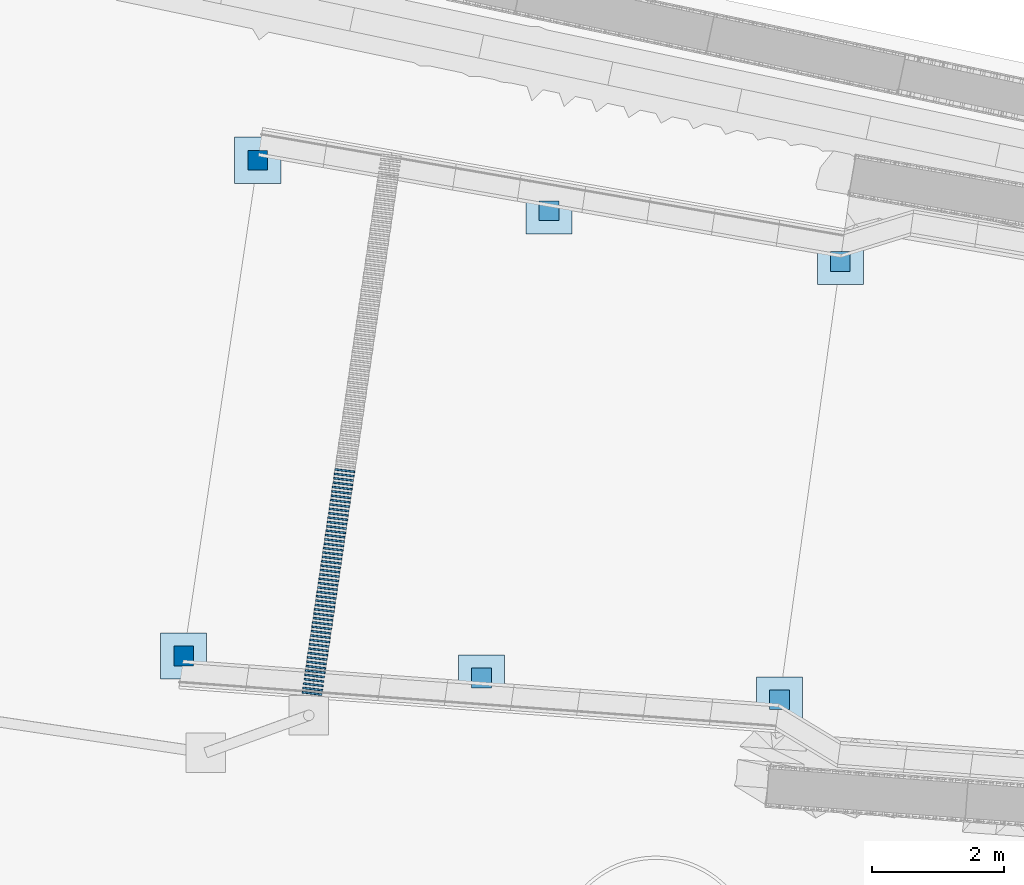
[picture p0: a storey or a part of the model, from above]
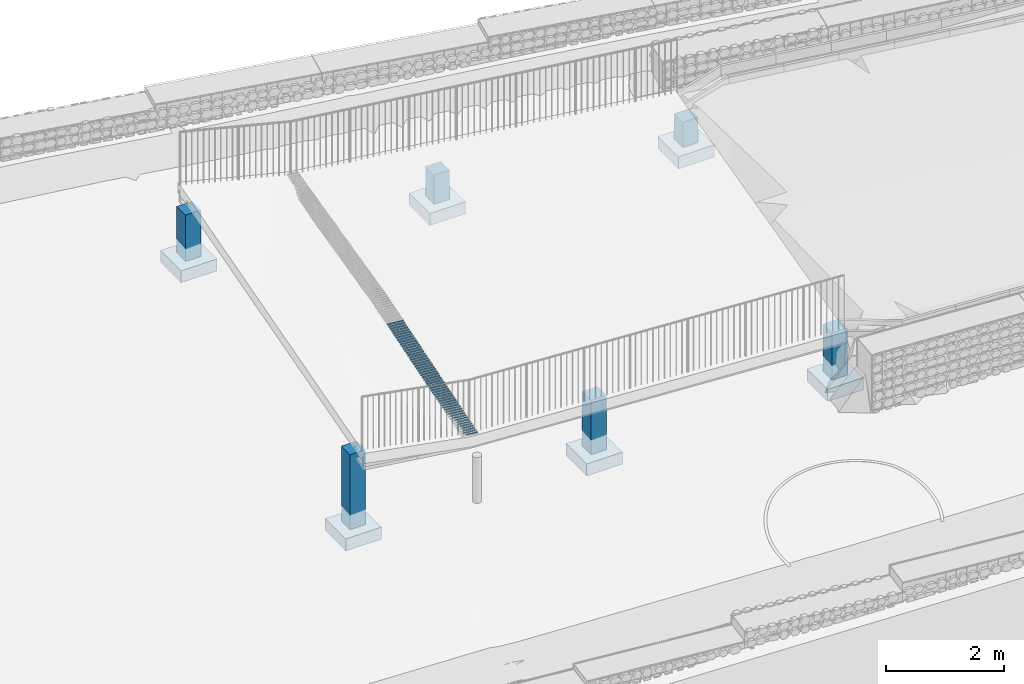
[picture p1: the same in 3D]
Properties of the parts of a building model (IFC4), part 2 of 3

# IfcBuildingElementProxy: Limite south · gabião 27 · pedra aparente
PredefinedType: USERDEFINED; Material: Gabião · pedra irregular
Pset_CasaProvenance - DesignSource: Casa Sobreposta / configuration.json; ReferenceFile: 260617_CasaDFL_Estrutura_Terreno.ifc; ConstructionBasis: DESIGN_ASSUMPTION; Note: R07 concept geometry; dimensions and connections not structurally verified.

# IfcBuildingElementProxy: Limite south · gabião 28 · cesto galvanizado
In: Lares · Rua das Mercês · artigo 4771
PredefinedType: USERDEFINED; Material: Aço galvanizado / Stahl verzinkt
Pset_CasaProvenance - DesignSource: Casa Sobreposta / configuration.json; ReferenceFile: 260617_CasaDFL_Estrutura_Terreno.ifc; ConstructionBasis: DESIGN_ASSUMPTION; Note: R07 concept geometry; dimensions and connections not structurally verified.

# IfcBuildingElementProxy: Limite south · gabião 28 · pedra aparente
In: Lares · Rua das Mercês · artigo 4771
PredefinedType: USERDEFINED; Material: Gabião · pedra irregular
Pset_CasaProvenance - DesignSource: Casa Sobreposta / configuration.json; ReferenceFile: 260617_CasaDFL_Estrutura_Terreno.ifc; ConstructionBasis: DESIGN_ASSUMPTION; Note: R07 concept geometry; dimensions and connections not structurally verified.

# IfcBuildingElementProxy: Limite south · gabião 29 · cesto galvanizado
In: Lares · Rua das Mercês · artigo 4771
PredefinedType: USERDEFINED; Material: Aço galvanizado / Stahl verzinkt
Pset_CasaProvenance - DesignSource: Casa Sobreposta / configuration.json; ReferenceFile: 260617_CasaDFL_Estrutura_Terreno.ifc; ConstructionBasis: DESIGN_ASSUMPTION; Note: R07 concept geometry; dimensions and connections not structurally verified.

# IfcBuildingElementProxy: Limite south · gabião 29 · pedra aparente
In: Lares · Rua das Mercês · artigo 4771
PredefinedType: USERDEFINED; Material: Gabião · pedra irregular
Pset_CasaProvenance - DesignSource: Casa Sobreposta / configuration.json; ReferenceFile: 260617_CasaDFL_Estrutura_Terreno.ifc; ConstructionBasis: DESIGN_ASSUMPTION; Note: R07 concept geometry; dimensions and connections not structurally verified.

# IfcBuildingElementProxy: Limite south · gabião 3 · cesto galvanizado
In: Lares · Rua das Mercês · artigo 4771
PredefinedType: USERDEFINED; Material: Aço galvanizado / Stahl verzinkt
Pset_CasaProvenance - DesignSource: Casa Sobreposta / configuration.json; ReferenceFile: 260617_CasaDFL_Estrutura_Terreno.ifc; ConstructionBasis: DESIGN_ASSUMPTION; Note: R07 concept geometry; dimensions and connections not structurally verified.

# IfcBuildingElementProxy: Limite south · gabião 3 · pedra aparente
In: Lares · Rua das Mercês · artigo 4771
PredefinedType: USERDEFINED; Material: Gabião · pedra irregular
Pset_CasaProvenance - DesignSource: Casa Sobreposta / configuration.json; ReferenceFile: 260617_CasaDFL_Estrutura_Terreno.ifc; ConstructionBasis: DESIGN_ASSUMPTION; Note: R07 concept geometry; dimensions and connections not structurally verified.

# IfcBuildingElementProxy: Limite south · gabião 30 · cesto galvanizado
In: Lares · Rua das Mercês · artigo 4771
PredefinedType: USERDEFINED; Material: Aço galvanizado / Stahl verzinkt
Pset_CasaProvenance - DesignSource: Casa Sobreposta / configuration.json; ReferenceFile: 260617_CasaDFL_Estrutura_Terreno.ifc; ConstructionBasis: DESIGN_ASSUMPTION; Note: R07 concept geometry; dimensions and connections not structurally verified.

# IfcBuildingElementProxy: Limite south · gabião 30 · pedra aparente
In: Lares · Rua das Mercês · artigo 4771
PredefinedType: USERDEFINED; Material: Gabião · pedra irregular
Pset_CasaProvenance - DesignSource: Casa Sobreposta / configuration.json; ReferenceFile: 260617_CasaDFL_Estrutura_Terreno.ifc; ConstructionBasis: DESIGN_ASSUMPTION; Note: R07 concept geometry; dimensions and connections not structurally verified.

# IfcBuildingElementProxy: Limite south · gabião 31 · cesto galvanizado
In: Lares · Rua das Mercês · artigo 4771
PredefinedType: USERDEFINED; Material: Aço galvanizado / Stahl verzinkt
Pset_CasaProvenance - DesignSource: Casa Sobreposta / configuration.json; ReferenceFile: 260617_CasaDFL_Estrutura_Terreno.ifc; ConstructionBasis: DESIGN_ASSUMPTION; Note: R07 concept geometry; dimensions and connections not structurally verified.

# IfcBuildingElementProxy: Limite south · gabião 31 · pedra aparente
In: Lares · Rua das Mercês · artigo 4771
PredefinedType: USERDEFINED; Material: Gabião · pedra irregular
Pset_CasaProvenance - DesignSource: Casa Sobreposta / configuration.json; ReferenceFile: 260617_CasaDFL_Estrutura_Terreno.ifc; ConstructionBasis: DESIGN_ASSUMPTION; Note: R07 concept geometry; dimensions and connections not structurally verified.

# IfcBuildingElementProxy: Limite south · gabião 4 · cesto galvanizado
In: Lares · Rua das Mercês · artigo 4771
PredefinedType: USERDEFINED; Material: Aço galvanizado / Stahl verzinkt
Pset_CasaProvenance - DesignSource: Casa Sobreposta / configuration.json; ReferenceFile: 260617_CasaDFL_Estrutura_Terreno.ifc; ConstructionBasis: DESIGN_ASSUMPTION; Note: R07 concept geometry; dimensions and connections not structurally verified.

# IfcBuildingElementProxy: Limite south · gabião 4 · pedra aparente
In: Lares · Rua das Mercês · artigo 4771
PredefinedType: USERDEFINED; Material: Gabião · pedra irregular
Pset_CasaProvenance - DesignSource: Casa Sobreposta / configuration.json; ReferenceFile: 260617_CasaDFL_Estrutura_Terreno.ifc; ConstructionBasis: DESIGN_ASSUMPTION; Note: R07 concept geometry; dimensions and connections not structurally verified.

# IfcBuildingElementProxy: Limite south · gabião 5 · cesto galvanizado
In: Lares · Rua das Mercês · artigo 4771
PredefinedType: USERDEFINED; Material: Aço galvanizado / Stahl verzinkt
Pset_CasaProvenance - DesignSource: Casa Sobreposta / configuration.json; ReferenceFile: 260617_CasaDFL_Estrutura_Terreno.ifc; ConstructionBasis: DESIGN_ASSUMPTION; Note: R07 concept geometry; dimensions and connections not structurally verified.

# IfcBuildingElementProxy: Limite south · gabião 5 · pedra aparente
In: Lares · Rua das Mercês · artigo 4771
PredefinedType: USERDEFINED; Material: Gabião · pedra irregular
Pset_CasaProvenance - DesignSource: Casa Sobreposta / configuration.json; ReferenceFile: 260617_CasaDFL_Estrutura_Terreno.ifc; ConstructionBasis: DESIGN_ASSUMPTION; Note: R07 concept geometry; dimensions and connections not structurally verified.

# IfcBuildingElementProxy: Limite south · gabião 6 · cesto galvanizado
In: Lares · Rua das Mercês · artigo 4771
PredefinedType: USERDEFINED; Material: Aço galvanizado / Stahl verzinkt
Pset_CasaProvenance - DesignSource: Casa Sobreposta / configuration.json; ReferenceFile: 260617_CasaDFL_Estrutura_Terreno.ifc; ConstructionBasis: DESIGN_ASSUMPTION; Note: R07 concept geometry; dimensions and connections not structurally verified.

# IfcBuildingElementProxy: Limite south · gabião 6 · pedra aparente
In: Lares · Rua das Mercês · artigo 4771
PredefinedType: USERDEFINED; Material: Gabião · pedra irregular
Pset_CasaProvenance - DesignSource: Casa Sobreposta / configuration.json; ReferenceFile: 260617_CasaDFL_Estrutura_Terreno.ifc; ConstructionBasis: DESIGN_ASSUMPTION; Note: R07 concept geometry; dimensions and connections not structurally verified.

# IfcBuildingElementProxy: Limite south · gabião 7 · cesto galvanizado
In: Lares · Rua das Mercês · artigo 4771
PredefinedType: USERDEFINED; Material: Aço galvanizado / Stahl verzinkt
Pset_CasaProvenance - DesignSource: Casa Sobreposta / configuration.json; ReferenceFile: 260617_CasaDFL_Estrutura_Terreno.ifc; ConstructionBasis: DESIGN_ASSUMPTION; Note: R07 concept geometry; dimensions and connections not structurally verified.

# IfcBuildingElementProxy: Limite south · gabião 7 · pedra aparente
In: Lares · Rua das Mercês · artigo 4771
PredefinedType: USERDEFINED; Material: Gabião · pedra irregular
Pset_CasaProvenance - DesignSource: Casa Sobreposta / configuration.json; ReferenceFile: 260617_CasaDFL_Estrutura_Terreno.ifc; ConstructionBasis: DESIGN_ASSUMPTION; Note: R07 concept geometry; dimensions and connections not structurally verified.

# IfcBuildingElementProxy: Limite south · gabião 8 · cesto galvanizado
In: Lares · Rua das Mercês · artigo 4771
PredefinedType: USERDEFINED; Material: Aço galvanizado / Stahl verzinkt
Pset_CasaProvenance - DesignSource: Casa Sobreposta / configuration.json; ReferenceFile: 260617_CasaDFL_Estrutura_Terreno.ifc; ConstructionBasis: DESIGN_ASSUMPTION; Note: R07 concept geometry; dimensions and connections not structurally verified.

# IfcBuildingElementProxy: Limite south · gabião 8 · pedra aparente
In: Lares · Rua das Mercês · artigo 4771
PredefinedType: USERDEFINED; Material: Gabião · pedra irregular
Pset_CasaProvenance - DesignSource: Casa Sobreposta / configuration.json; ReferenceFile: 260617_CasaDFL_Estrutura_Terreno.ifc; ConstructionBasis: DESIGN_ASSUMPTION; Note: R07 concept geometry; dimensions and connections not structurally verified.

# IfcBuildingElementProxy: Limite south · gabião 9 · cesto galvanizado
In: Lares · Rua das Mercês · artigo 4771
PredefinedType: USERDEFINED; Material: Aço galvanizado / Stahl verzinkt
Pset_CasaProvenance - DesignSource: Casa Sobreposta / configuration.json; ReferenceFile: 260617_CasaDFL_Estrutura_Terreno.ifc; ConstructionBasis: DESIGN_ASSUMPTION; Note: R07 concept geometry; dimensions and connections not structurally verified.

# IfcBuildingElementProxy: Limite south · gabião 9 · pedra aparente
In: Lares · Rua das Mercês · artigo 4771
PredefinedType: USERDEFINED; Material: Gabião · pedra irregular
Pset_CasaProvenance - DesignSource: Casa Sobreposta / configuration.json; ReferenceFile: 260617_CasaDFL_Estrutura_Terreno.ifc; ConstructionBasis: DESIGN_ASSUMPTION; Note: R07 concept geometry; dimensions and connections not structurally verified.

# IfcBuildingElementProxy: Limite south · vala de interceção (46)
In: Lares · Rua das Mercês · artigo 4771
PredefinedType: USERDEFINED; Material: Brita drenante
Pset_CasaProvenance - DesignSource: Casa Sobreposta / configuration.json; ReferenceFile: 260617_CasaDFL_Estrutura_Terreno.ifc; ConstructionBasis: DESIGN_ASSUMPTION

# IfcBuildingElementProxy: Trepadeiras · floreira (10)
In: 00 · Habitação e estacionamento
PredefinedType: USERDEFINED; Material: Betão armado / Stahlbeton
Pset_CasaProvenance - DesignSource: Casa Sobreposta / configuration.json; ReferenceFile: 260617_CasaDFL_Estrutura_Terreno.ifc; ConstructionBasis: DESIGN_ASSUMPTION; Note: Indicative planter; soil volume, irrigation, root space and waterproofing to design.

# IfcColumn (57)
Material: Betão armado / Stahlbeton
Pset_CasaProvenance - DesignSource: Casa Sobreposta / configuration.json; ReferenceFile: 260617_CasaDFL_Estrutura_Terreno.ifc
Name | In | ConstructionBasis
18 x Casa térrea · pedestal | 00 · Habitação e estacionamento | ADAPTED_REFERENCE
33 x Pódio suspenso · apoio sobre o terreno | 00 · Habitação e estacionamento | DESIGN_ASSUMPTION
6 x Acesso · apoio do tabuleiro | Lares · Rua das Mercês · artigo 4771 | DESIGN_ASSUMPTION

# IfcColumn: IPE240 / steel (18)
In: 00 · Habitação e estacionamento
Type - Material: Aço pintado / Stahl lackiert
Pset_CasaProvenance - DesignSource: Casa Sobreposta / configuration.json; ReferenceFile: 260617_CasaDFL_Estrutura_Terreno.ifc; ConstructionBasis: ADAPTED_REFERENCE; Note: Reference section; spans, stability and connections require design.

# IfcColumn: RHS80x60x4 / steel (4)
In: 00 · Habitação e estacionamento
Type - Material: Aço pintado / Stahl lackiert
Pset_CasaProvenance - DesignSource: Casa Sobreposta / configuration.json; ReferenceFile: 260617_CasaDFL_Estrutura_Terreno.ifc; ConstructionBasis: DESIGN_ASSUMPTION; Note: Reference section; spans, stability and connections require design.

# IfcColumn: TIMBER0.160x0.160 / timber (24)
In: 00 · Habitação e estacionamento
Type - Material: Madeira / Bauholz
Pset_CasaProvenance - DesignSource: Casa Sobreposta / configuration.json; ReferenceFile: 260617_CasaDFL_Estrutura_Terreno.ifc; ConstructionBasis: DESIGN_ASSUMPTION; Note: Visible timber concept; strength class, deflection, stability, wind and fire design pending.

# IfcCovering (15)
Pset_CasaProvenance - DesignSource: Casa Sobreposta / configuration.json; ReferenceFile: 260617_CasaDFL_Estrutura_Terreno.ifc; ConstructionBasis: DESIGN_ASSUMPTION
Name | In | PredefinedType | Material
2 x Cobertura · forro de madeira | 00 · Habitação e estacionamento | CLADDING | Madeira / Bauholz
2 x Cobertura · isolamento | 00 · Habitação e estacionamento | INSULATION | Lã mineral / Mineralwolle 2
2 x Cobertura · membrana | 00 · Habitação e estacionamento | MEMBRANE | Membrana impermeável — hipótese
Cobertura · telhas individualizadas 1 | 00 · Habitação e estacionamento | ROOFING | Telha cerâmica · tile0 | Pset_CasaProvenance - Note: R07 concept geometry; dimensions and connections not structurally verified.
Cobertura · telhas individualizadas 2 | 00 · Habitação e estacionamento | ROOFING | Telha cerâmica · tile1 | Pset_CasaProvenance - Note: R07 concept geometry; dimensions and connections not structurally verified.
Cobertura · telhas individualizadas 3 | 00 · Habitação e estacionamento | ROOFING | Telha cerâmica · tile2 | Pset_CasaProvenance - Note: R07 concept geometry; dimensions and connections not structurally verified.
Cobertura · cumeeira cerâmica | 00 · Habitação e estacionamento | ROOFING | Telha cerâmica · tile1
Cisterna · camada drenante 100 mm | -01 · Cisterna sob o terraço | FLOORING | Brita drenante
Cisterna · impermeabilização poente | -01 · Cisterna sob o terraço | MEMBRANE | Membrana impermeável — hipótese
Cisterna · impermeabilização norte | -01 · Cisterna sob o terraço | MEMBRANE | Membrana impermeável — hipótese
Cisterna · impermeabilização sul | -01 · Cisterna sob o terraço | MEMBRANE | Membrana impermeável — hipótese
Cisterna · impermeabilização nascente | -01 · Cisterna sob o terraço | MEMBRANE | Membrana impermeável — hipótese

# IfcDoor (18)
In: 00 · Habitação e estacionamento
PredefinedType: DOOR
Pset_CasaProvenance - DesignSource: Casa Sobreposta / configuration.json; ReferenceFile: 260617_CasaDFL_Estrutura_Terreno.ifc
Name | OverallHeight (m) | OverallWidth (m) | OperationType | Material | ConstructionBasis
Porta interior 1 | 2.1 | 0.830093 | SINGLE_SWING_LEFT | OSB | ADAPTED_REFERENCE
Porta interior 2 | 2.1 | 0.830093 | SINGLE_SWING_LEFT | OSB | ADAPTED_REFERENCE
Porta interior 3 | 2.1 | 0.730086 | SINGLE_SWING_LEFT | OSB | ADAPTED_REFERENCE
Porta interior 4 | 2.1 | 0.830092 | SINGLE_SWING_LEFT | OSB | ADAPTED_REFERENCE
Porta interior 5 | 2.1 | 0.830077 | SINGLE_SWING_LEFT | OSB | ADAPTED_REFERENCE
Porta interior 6 | 2.1 | 0.730017 | SINGLE_SWING_LEFT | OSB | ADAPTED_REFERENCE
Porta do estacionamento | 2.1 | 0.83 | SINGLE_SWING_LEFT | Aço pintado / Stahl lackiert | ADAPTED_REFERENCE
Folha de correr sul 2 | 3 | 1.97133 | SLIDING_TO_LEFT | Vidro / Normalglas | DESIGN_ASSUMPTION
Folha de correr sul 4 | 3 | 1.97133 | SLIDING_TO_LEFT | Vidro / Normalglas | DESIGN_ASSUMPTION
Folha de correr sul 6 | 3 | 1.97133 | SLIDING_TO_LEFT | Vidro / Normalglas | DESIGN_ASSUMPTION
Folha de correr sul 8 | 3 | 1.97133 | SLIDING_TO_LEFT | Vidro / Normalglas | DESIGN_ASSUMPTION
Folha de correr sul 10 | 3 | 1.97133 | SLIDING_TO_LEFT | Vidro / Normalglas | DESIGN_ASSUMPTION
Folha de correr sul 12 | 3 | 0.614 | SLIDING_TO_LEFT | Vidro / Normalglas | DESIGN_ASSUMPTION
Fachada poente integralmente envidraçada · módulo 4 | 3 | 1.55 | SLIDING_TO_LEFT | Vidro / Normalglas | DESIGN_ASSUMPTION | Pset_CasaGlazedFacade - Revision: R02 · kiwi pergola; Facade: WEST / highlighted end in user sketch; Infill: Full-height glazing; no opaque infill; GlazingSpecification: 8 mm nominal representation only; insulated safety glazing assembly to specify
2 x Contentor · porta dupla | 2.39 | 1.17 | SINGLE_SWING_LEFT | Contentor · pintura 1 | DESIGN_ASSUMPTION
2 x Contentor · porta dupla | 2.39 | 1.17 | SINGLE_SWING_LEFT | Contentor · pintura 2 | DESIGN_ASSUMPTION

# IfcElementAssembly: Acesso · guarda lateral do troço suspenso (6)
In: Lares · Rua das Mercês · artigo 4771
PredefinedType: USERDEFINED
Pset_CasaProvenance - DesignSource: Casa Sobreposta / configuration.json; ReferenceFile: 260617_CasaDFL_Estrutura_Terreno.ifc; ConstructionBasis: DESIGN_ASSUMPTION

# IfcElementAssembly: CISTERN_PODIUM, Pódio · terraço, casa térrea e cisterna
In: 00 · Habitação e estacionamento
PredefinedType: USERDEFINED
Pset_CasaProvenance - DesignSource: Casa Sobreposta / configuration.json; ReferenceFile: 260617_CasaDFL_Estrutura_Terreno.ifc; ConstructionBasis: DESIGN_ASSUMPTION
Pset_CasaUndercroft - NaturalGroundRetained: yes; EnclosedStorage: no; Use: Open ventilated sloping void; not a habitable or storage storey; StructuralStatus: Concept slab, beams, piers and foundation sizes; geotechnical and structural design pending
Pset_CasaPodium - TankGrossPlan_m2: 23; TankBaseLevel_m: 13.2; MinimumInternalHeight_m: 2.31; FloorSupport: Entire podium suspended on discrete supports above natural slope; PlanningAssumption: Cistern excluded from 250 m2 by explicit user confirmation 2026-10-02

# IfcElementAssembly: COVERED_PODIUM_BALCONY, Varanda coberta · continuação integral da cobertura
In: 00 · Habitação e estacionamento
PredefinedType: USERDEFINED
Pset_CasaProvenance - DesignSource: Casa Sobreposta / configuration.json; ReferenceFile: 260617_CasaDFL_Estrutura_Terreno.ifc; ConstructionBasis: DESIGN_ASSUMPTION

# IfcElementAssembly: EXISTING_SHIPPING_CONTAINER (2)
In: 00 · Habitação e estacionamento
PredefinedType: USERDEFINED
Pset_CasaProvenance - DesignSource: Casa Sobreposta / configuration.json; ReferenceFile: 260617_CasaDFL_Estrutura_Terreno.ifc; ConstructionBasis: DESIGN_ASSUMPTION
Pset_CasaExistingContext - Length_m: 6; WidthAssumed_m: 2.44; HeightAssumed_m: 2.59; Location: Digitised visible roofs from signed orthophoto; fitted 6 x 2.44 m, provisional +/- 0.50 m, verify ground corners; Status: Existing context; not included in new building setback or new floor-area schedule; Colour: Illustrative, condition not surveyed
Name
Contentor existente 1 · 6 m
Contentor existente 2 · 6 m

# IfcElementAssembly: LIVING_SHADE_TRELLIS, Fachada sul e pátio · estrutura e trepadeiras
In: 00 · Habitação e estacionamento
PredefinedType: USERDEFINED
Pset_CasaProvenance - DesignSource: Casa Sobreposta / configuration.json; ReferenceFile: 260617_CasaDFL_Estrutura_Terreno.ifc; ConstructionBasis: DESIGN_ASSUMPTION

# IfcFooting (73)
Material: Betão armado / Stahlbeton
Pset_CasaProvenance - DesignSource: Casa Sobreposta / configuration.json; ReferenceFile: 260617_CasaDFL_Estrutura_Terreno.ifc
Name | In | PredefinedType | ConstructionBasis
18 x Casa térrea · sapata | 00 · Habitação e estacionamento | PAD_FOOTING | ADAPTED_REFERENCE
Cisterna · sapata corrida poente | -01 · Cisterna sob o terraço | STRIP_FOOTING | DESIGN_ASSUMPTION
Cisterna · sapata corrida norte | -01 · Cisterna sob o terraço | STRIP_FOOTING | DESIGN_ASSUMPTION
Cisterna · sapata corrida sul | -01 · Cisterna sob o terraço | STRIP_FOOTING | DESIGN_ASSUMPTION
Cisterna · sapata corrida nascente | -01 · Cisterna sob o terraço | STRIP_FOOTING | DESIGN_ASSUMPTION
4 x Jardim · apoio | 00 · Habitação e estacionamento | PAD_FOOTING | DESIGN_ASSUMPTION
33 x Pódio suspenso · sapata pontual | 00 · Habitação e estacionamento | PAD_FOOTING | DESIGN_ASSUMPTION
8 x Contentor · apoio existente indicativo | 00 · Habitação e estacionamento | PAD_FOOTING | DESIGN_ASSUMPTION
6 x Acesso · sapata pontual | Lares · Rua das Mercês · artigo 4771 | PAD_FOOTING | DESIGN_ASSUMPTION

# IfcFurnishingElement, Ilha da cozinha · esquema
In: 00 · Habitação e estacionamento
Material: OSB
Pset_CasaProvenance - DesignSource: Casa Sobreposta / configuration.json; ReferenceFile: 260617_CasaDFL_Estrutura_Terreno.ifc; ConstructionBasis: ADAPTED_REFERENCE

# IfcGeographicElement, Terreno · R07 com telha, cisterna e drenagem
In: Lares · Rua das Mercês · artigo 4771
PredefinedType: TERRAIN; Material: Terreno · modelação proposta
Pset_CasaProvenance - DesignSource: Casa Sobreposta / configuration.json; ReferenceFile: 260617_CasaDFL_Estrutura_Terreno.ifc; ConstructionBasis: DESIGN_ASSUMPTION

# IfcGeographicElement: ANALYTICAL_CUT_VOLUME, Escavação · diferença entre terrenos
In: Lares · Rua das Mercês · artigo 4771
PredefinedType: USERDEFINED; Material: Escavação · volume analítico
Pset_CasaProvenance - DesignSource: Casa Sobreposta / configuration.json; ReferenceFile: 260617_CasaDFL_Estrutura_Terreno.ifc; ConstructionBasis: DESIGN_ASSUMPTION; Note: ANALYTICAL VOLUME, not additional constructed material. Closed wedges between surveyed and proposed TIN, split where sign changes. Excludes stripping, foundations, services and bulking.
Pset_CasaEarthworks - Kind: CUT; Volume_m3: 45.8495; Method: Exact signed integration of linear proposed/existing display TIN, splitting zero crossings; Excluded: Topsoil stripping, foundation/service trenches, soil replacement, bulking and shrinkage; Status: CONCEPT_GEOMETRIC_VOLUME; not a measured bill of works; DefaultVisibility: Hide analytical volumes in normal model views
Qto_CasaEarthworks - NetVolume: 45.8495 m3

# IfcGeographicElement: ANALYTICAL_FILL_VOLUME, Aterro · diferença entre terrenos
In: Lares · Rua das Mercês · artigo 4771
PredefinedType: USERDEFINED; Material: Aterro · volume analítico
Pset_CasaProvenance - DesignSource: Casa Sobreposta / configuration.json; ReferenceFile: 260617_CasaDFL_Estrutura_Terreno.ifc; ConstructionBasis: DESIGN_ASSUMPTION; Note: ANALYTICAL VOLUME, not additional constructed material. Closed wedges between surveyed and proposed TIN, split where sign changes. Excludes stripping, foundations, services and bulking.
Pset_CasaEarthworks - Kind: FILL; Volume_m3: 34.1829; Method: Exact signed integration of linear proposed/existing display TIN, splitting zero crossings; Excluded: Topsoil stripping, foundation/service trenches, soil replacement, bulking and shrinkage; Status: CONCEPT_GEOMETRIC_VOLUME; not a measured bill of works; DefaultVisibility: Hide analytical volumes in normal model views
Qto_CasaEarthworks - NetVolume: 34.1829 m3

# IfcGeographicElement: Acesso trapezoidal · 8,60 m no pódio / 5,00 m na rua
In: Lares · Rua das Mercês · artigo 4771
PredefinedType: USERDEFINED; Material: Pavimento rugoso · betão vassourado
Pset_CasaProvenance - DesignSource: Casa Sobreposta / configuration.json; ReferenceFile: 260617_CasaDFL_Estrutura_Terreno.ifc; ConstructionBasis: DESIGN_ASSUMPTION

# IfcGeographicElement: Marcação no solo · árvore indicativa 01
In: Lares · Rua das Mercês · artigo 4771
PredefinedType: USERDEFINED; Material: Marcação de plantação · linha no terreno
Pset_CasaProvenance - DesignSource: Casa Sobreposta / configuration.json; ReferenceFile: 260617_CasaDFL_Estrutura_Terreno.ifc; ConstructionBasis: DESIGN_ASSUMPTION; Note: R07 concept geometry; dimensions and connections not structurally verified.
Pset_PlantingReserve - Diameter_m: 3; Representation: GROUND_CIRCLE_ONLY; Species: UNSPECIFIED; Status: Indicative position and spacing, not a mature canopy guarantee

# IfcGeographicElement: Marcação no solo · árvore indicativa 02
In: Lares · Rua das Mercês · artigo 4771
PredefinedType: USERDEFINED; Material: Marcação de plantação · linha no terreno
Pset_CasaProvenance - DesignSource: Casa Sobreposta / configuration.json; ReferenceFile: 260617_CasaDFL_Estrutura_Terreno.ifc; ConstructionBasis: DESIGN_ASSUMPTION; Note: R07 concept geometry; dimensions and connections not structurally verified.
Pset_PlantingReserve - Diameter_m: 3; Representation: GROUND_CIRCLE_ONLY; Species: UNSPECIFIED; Status: Indicative position and spacing, not a mature canopy guarantee

# IfcGeographicElement: Marcação no solo · árvore indicativa 03
In: Lares · Rua das Mercês · artigo 4771
PredefinedType: USERDEFINED; Material: Marcação de plantação · linha no terreno
Pset_CasaProvenance - DesignSource: Casa Sobreposta / configuration.json; ReferenceFile: 260617_CasaDFL_Estrutura_Terreno.ifc; ConstructionBasis: DESIGN_ASSUMPTION; Note: R07 concept geometry; dimensions and connections not structurally verified.
Pset_PlantingReserve - Diameter_m: 3; Representation: GROUND_CIRCLE_ONLY; Species: UNSPECIFIED; Status: Indicative position and spacing, not a mature canopy guarantee

# IfcGeographicElement: Marcação no solo · árvore indicativa 04
In: Lares · Rua das Mercês · artigo 4771
PredefinedType: USERDEFINED; Material: Marcação de plantação · linha no terreno
Pset_CasaProvenance - DesignSource: Casa Sobreposta / configuration.json; ReferenceFile: 260617_CasaDFL_Estrutura_Terreno.ifc; ConstructionBasis: DESIGN_ASSUMPTION; Note: R07 concept geometry; dimensions and connections not structurally verified.
Pset_PlantingReserve - Diameter_m: 3; Representation: GROUND_CIRCLE_ONLY; Species: UNSPECIFIED; Status: Indicative position and spacing, not a mature canopy guarantee

# IfcGeographicElement: Marcação no solo · árvore indicativa 05
In: Lares · Rua das Mercês · artigo 4771
PredefinedType: USERDEFINED; Material: Marcação de plantação · linha no terreno
Pset_CasaProvenance - DesignSource: Casa Sobreposta / configuration.json; ReferenceFile: 260617_CasaDFL_Estrutura_Terreno.ifc; ConstructionBasis: DESIGN_ASSUMPTION; Note: R07 concept geometry; dimensions and connections not structurally verified.
Pset_PlantingReserve - Diameter_m: 3; Representation: GROUND_CIRCLE_ONLY; Species: UNSPECIFIED; Status: Indicative position and spacing, not a mature canopy guarantee

# IfcGeographicElement: Marcação no solo · árvore indicativa 06
In: Lares · Rua das Mercês · artigo 4771
PredefinedType: USERDEFINED; Material: Marcação de plantação · linha no terreno
Pset_CasaProvenance - DesignSource: Casa Sobreposta / configuration.json; ReferenceFile: 260617_CasaDFL_Estrutura_Terreno.ifc; ConstructionBasis: DESIGN_ASSUMPTION; Note: R07 concept geometry; dimensions and connections not structurally verified.
Pset_PlantingReserve - Diameter_m: 3; Representation: GROUND_CIRCLE_ONLY; Species: UNSPECIFIED; Status: Indicative position and spacing, not a mature canopy guarantee

# IfcGeographicElement: Marcação no solo · árvore indicativa 07
In: Lares · Rua das Mercês · artigo 4771
PredefinedType: USERDEFINED; Material: Marcação de plantação · linha no terreno
Pset_CasaProvenance - DesignSource: Casa Sobreposta / configuration.json; ReferenceFile: 260617_CasaDFL_Estrutura_Terreno.ifc; ConstructionBasis: DESIGN_ASSUMPTION; Note: R07 concept geometry; dimensions and connections not structurally verified.
Pset_PlantingReserve - Diameter_m: 3; Representation: GROUND_CIRCLE_ONLY; Species: UNSPECIFIED; Status: Indicative position and spacing, not a mature canopy guarantee

# IfcGeographicElement: Marcação no solo · árvore indicativa 08
In: Lares · Rua das Mercês · artigo 4771
PredefinedType: USERDEFINED; Material: Marcação de plantação · linha no terreno
Pset_CasaProvenance - DesignSource: Casa Sobreposta / configuration.json; ReferenceFile: 260617_CasaDFL_Estrutura_Terreno.ifc; ConstructionBasis: DESIGN_ASSUMPTION; Note: R07 concept geometry; dimensions and connections not structurally verified.
Pset_PlantingReserve - Diameter_m: 3; Representation: GROUND_CIRCLE_ONLY; Species: UNSPECIFIED; Status: Indicative position and spacing, not a mature canopy guarantee

# IfcGeographicElement: Marcação no solo · árvore indicativa 09
In: Lares · Rua das Mercês · artigo 4771
PredefinedType: USERDEFINED; Material: Marcação de plantação · linha no terreno
Pset_CasaProvenance - DesignSource: Casa Sobreposta / configuration.json; ReferenceFile: 260617_CasaDFL_Estrutura_Terreno.ifc; ConstructionBasis: DESIGN_ASSUMPTION; Note: R07 concept geometry; dimensions and connections not structurally verified.
Pset_PlantingReserve - Diameter_m: 3; Representation: GROUND_CIRCLE_ONLY; Species: UNSPECIFIED; Status: Indicative position and spacing, not a mature canopy guarantee

# IfcGeographicElement: Marcação no solo · árvore indicativa 10
In: Lares · Rua das Mercês · artigo 4771
PredefinedType: USERDEFINED; Material: Marcação de plantação · linha no terreno
Pset_CasaProvenance - DesignSource: Casa Sobreposta / configuration.json; ReferenceFile: 260617_CasaDFL_Estrutura_Terreno.ifc; ConstructionBasis: DESIGN_ASSUMPTION; Note: R07 concept geometry; dimensions and connections not structurally verified.
Pset_PlantingReserve - Diameter_m: 3; Representation: GROUND_CIRCLE_ONLY; Species: UNSPECIFIED; Status: Indicative position and spacing, not a mature canopy guarantee

# IfcGeographicElement: VEGETATION, Trepadeiras · folhas individuais, estado ilustrativo
In: 00 · Habitação e estacionamento
PredefinedType: USERDEFINED; Material: Folhagem · trepadeiras
Pset_CasaProvenance - DesignSource: Casa Sobreposta / configuration.json; ReferenceFile: 260617_CasaDFL_Estrutura_Terreno.ifc; ConstructionBasis: DESIGN_ASSUMPTION; Note: Procedural leaves for visual intent only; no predicted growth, species performance or wind protection.

# IfcMember (154)
In: 00 · Habitação e estacionamento
Pset_CasaProvenance - DesignSource: Casa Sobreposta / configuration.json; ReferenceFile: 260617_CasaDFL_Estrutura_Terreno.ifc; ConstructionBasis: DESIGN_ASSUMPTION
Name | Material
4 x Contentor · canto | Contentor · pintura 1
50 x Contentor · nervura lateral | Contentor · pintura 1
23 x Contentor · nervura cobertura | Contentor · pintura 1
4 x Contentor · canto | Contentor · pintura 2
50 x Contentor · nervura lateral | Contentor · pintura 2
23 x Contentor · nervura cobertura | Contentor · pintura 2

# IfcMember: C240 / steel (2)
In: 00 · Habitação e estacionamento
Type - Material: Aço pintado / Stahl lackiert
Pset_CasaProvenance - DesignSource: Casa Sobreposta / configuration.json; ReferenceFile: 260617_CasaDFL_Estrutura_Terreno.ifc; ConstructionBasis: ADAPTED_REFERENCE; Note: Reference section; spans, stability and connections require design.

# IfcMember: D0.004 / galvanized (117)
In: 00 · Habitação e estacionamento
Type - Material: Aço galvanizado / Stahl verzinkt
Pset_CasaProvenance - DesignSource: Casa Sobreposta / configuration.json; ReferenceFile: 260617_CasaDFL_Estrutura_Terreno.ifc; ConstructionBasis: DESIGN_ASSUMPTION; Note: Reference section; spans, stability and connections require design.
Name
50 x Trepadeiras · fio horizontal
67 x Trepadeiras · fio vertical

# IfcMember: D0.015 / vine_wood (627)
In: 00 · Habitação e estacionamento
Type - Material: Ramos de trepadeiras
Pset_CasaProvenance - DesignSource: Casa Sobreposta / configuration.json; ReferenceFile: 260617_CasaDFL_Estrutura_Terreno.ifc; ConstructionBasis: DESIGN_ASSUMPTION; Note: Reference section; spans, stability and connections require design.

# IfcMember: D0.025 / galvanized (8)
In: 00 · Habitação e estacionamento
Type - Material: Aço galvanizado / Stahl verzinkt
Pset_CasaProvenance - DesignSource: Casa Sobreposta / configuration.json; ReferenceFile: 260617_CasaDFL_Estrutura_Terreno.ifc; ConstructionBasis: DESIGN_ASSUMPTION; Note: Reference section; spans, stability and connections require design.

# IfcMember: R0.025 / galvanized (212)
Type - Material: Aço galvanizado / Stahl verzinkt
Pset_CasaProvenance - DesignSource: Casa Sobreposta / configuration.json; ReferenceFile: 260617_CasaDFL_Estrutura_Terreno.ifc; ConstructionBasis: DESIGN_ASSUMPTION; Note: Reference section; spans, stability and connections require design.
Name | In
8 x Cobertura · fita de contraventamento | 00 · Habitação e estacionamento
80 x Interceção · grelha rua | Lares · Rua das Mercês · artigo 4771
124 x Interceção · grelha estacionamento | Lares · Rua das Mercês · artigo 4771

# IfcMember: R0.035 / steel (68)
In: 00 · Habitação e estacionamento
Type - Material: Aço pintado / Stahl lackiert
Pset_CasaProvenance - DesignSource: Casa Sobreposta / configuration.json; ReferenceFile: 260617_CasaDFL_Estrutura_Terreno.ifc; ConstructionBasis: ADAPTED_REFERENCE; Note: Reference section; spans, stability and connections require design.
Name
2 x Rasgo norte 1 · montante
2 x Rasgo norte 1 · travessa
2 x Rasgo norte 2 · montante
2 x Rasgo norte 2 · travessa
2 x Rasgo norte 3 · montante
2 x Rasgo norte 3 · travessa
2 x Rasgo norte 4 · montante
2 x Rasgo norte 4 · travessa
2 x Rasgo norte 5 · montante
2 x Rasgo norte 5 · travessa
2 x Rasgo norte 6 · montante
2 x Rasgo norte 6 · travessa
2 x Rasgo norte 7 · montante
2 x Rasgo norte 7 · travessa
2 x Folha de correr sul 2 · montante
2 x Folha de correr sul 2 · travessa
2 x Folha de correr sul 4 · montante
2 x Folha de correr sul 4 · travessa
2 x Folha de correr sul 6 · montante
2 x Folha de correr sul 6 · travessa
2 x Folha de correr sul 8 · montante
2 x Folha de correr sul 8 · travessa
2 x Folha de correr sul 10 · montante
2 x Folha de correr sul 10 · travessa
2 x Folha de correr sul 12 · montante
2 x Folha de correr sul 12 · travessa
2 x Fachada poente integralmente envidraçada · módulo 1 · montante
2 x Fachada poente integralmente envidraçada · módulo 1 · travessa
2 x Fachada poente integralmente envidraçada · módulo 2 · montante
2 x Fachada poente integralmente envidraçada · módulo 2 · travessa
2 x Fachada poente integralmente envidraçada · módulo 3 · montante
2 x Fachada poente integralmente envidraçada · módulo 3 · travessa
2 x Fachada poente integralmente envidraçada · módulo 4 · montante
2 x Fachada poente integralmente envidraçada · módulo 4 · travessa

# IfcMember: TIMBER0.045x0.060 / timber (30)
In: 00 · Habitação e estacionamento
Type - Material: Madeira / Bauholz
Pset_CasaProvenance - DesignSource: Casa Sobreposta / configuration.json; ReferenceFile: 260617_CasaDFL_Estrutura_Terreno.ifc; ConstructionBasis: DESIGN_ASSUMPTION; Note: Visible timber concept; strength class, deflection, stability, wind and fire design pending.

# IfcMember: TIMBER0.080x0.240 / timber (134)
In: 00 · Habitação e estacionamento
Type - Material: Madeira / Bauholz
Pset_CasaProvenance - DesignSource: Casa Sobreposta / configuration.json; ReferenceFile: 260617_CasaDFL_Estrutura_Terreno.ifc; ConstructionBasis: DESIGN_ASSUMPTION; Note: Visible timber concept; strength class, deflection, stability, wind and fire design pending.

# IfcMember: TIMBER0.100x0.160 / timber (24)
In: 00 · Habitação e estacionamento
Type - Material: Madeira / Bauholz
Pset_CasaProvenance - DesignSource: Casa Sobreposta / configuration.json; ReferenceFile: 260617_CasaDFL_Estrutura_Terreno.ifc; ConstructionBasis: DESIGN_ASSUMPTION; Note: Visible timber concept; strength class, deflection, stability, wind and fire design pending.

# IfcMember: TIMBER0.140x0.140 / timber (12)
In: 00 · Habitação e estacionamento
Type - Material: Madeira / Bauholz
Pset_CasaProvenance - DesignSource: Casa Sobreposta / configuration.json; ReferenceFile: 260617_CasaDFL_Estrutura_Terreno.ifc; ConstructionBasis: DESIGN_ASSUMPTION; Note: Visible timber concept; strength class, deflection, stability, wind and fire design pending.

# IfcMember: TIMBER0.160x0.240 / timber (24)
In: 00 · Habitação e estacionamento
Type - Material: Madeira / Bauholz
Pset_CasaProvenance - DesignSource: Casa Sobreposta / configuration.json; ReferenceFile: 260617_CasaDFL_Estrutura_Terreno.ifc; ConstructionBasis: DESIGN_ASSUMPTION; Note: Visible timber concept; strength class, deflection, stability, wind and fire design pending.

# IfcOpeningElement (20)
In: 00 · Habitação e estacionamento
PredefinedType: OPENING
Pset_CasaProvenance - DesignSource: Casa Sobreposta / configuration.json; ReferenceFile: 260617_CasaDFL_Estrutura_Terreno.ifc; ConstructionBasis: DESIGN_ASSUMPTION; Note: Real subtractive void
Name
Vão porta interior 1.1
Vão porta interior 1.2
Vão porta interior 2.1
Vão porta interior 2.2
Vão porta interior 3.1
Vão porta interior 3.2
Vão porta interior 4.1
Vão porta interior 4.2
Vão porta interior 5.1
Vão porta interior 6.1
Vão porta interior 6.2
Vão rasgo norte 1
Vão rasgo norte 2
Vão rasgo norte 3
Vão rasgo norte 4
Vão rasgo norte 5
Vão rasgo norte 6
Vão rasgo norte 7
Vão de acesso do estacionamento
Cisterna · abertura de inspeção

# IfcPipeSegment: D0.10 / galvanized (6)
In: 00 · Habitação e estacionamento
Type - Material: Aço galvanizado / Stahl verzinkt
Pset_CasaProvenance - DesignSource: Casa Sobreposta / configuration.json; ReferenceFile: 260617_CasaDFL_Estrutura_Terreno.ifc; ConstructionBasis: DESIGN_ASSUMPTION; Note: Nominal route to rainwater tank; Nominal gutter fall 0.2% to west; filter, first flush, sizing and overflow to detail. Separate from vehicle drainage.

# IfcPipeSegment: D0.16 / drain (4)
In: Lares · Rua das Mercês · artigo 4771
Type - Material: Caleiras · betão
Pset_CasaProvenance - DesignSource: Casa Sobreposta / configuration.json; ReferenceFile: 260617_CasaDFL_Estrutura_Terreno.ifc; ConstructionBasis: DESIGN_ASSUMPTION
Name | Note
Acesso · queda pluvial até coletor | Reference section; spans, stability and connections require design.
3 x Acesso · coletor separado da cisterna | Nominal DN160 spatial route only, not hydraulically sized. Silt/contaminant treatment and outlet/infiltration to design.

# IfcPlate (50)
In: 00 · Habitação e estacionamento
Pset_CasaProvenance - DesignSource: Casa Sobreposta / configuration.json; ReferenceFile: 260617_CasaDFL_Estrutura_Terreno.ifc; ConstructionBasis: DESIGN_ASSUMPTION
Name | PredefinedType | Material
18 x Cobertura · ligação madeira aço | SHEET | Aço galvanizado / Stahl verzinkt
Empena poente envidraçada | SHEET | Vidro / Normalglas
Cisterna · tampa estanque de inspeção | SHEET | Aço galvanizado / Stahl verzinkt | Pset_CasaProvenance - Note: Flush, closed 900 mm maintenance hatch; cover capacity and safe maintenance access to detail. Not a routine entrance.
24 x Varanda coberta · base metálica | SHEET | Aço galvanizado / Stahl verzinkt
2 x Contentor · chapa lateral |  | Contentor · pintura 1
Contentor · chapa de fundo |  | Contentor · pintura 1
2 x Contentor · chapa lateral |  | Contentor · pintura 2
Contentor · chapa de fundo |  | Contentor · pintura 2

# IfcRailing (14)
PredefinedType: GUARDRAIL; Material: Aço pintado / Stahl lackiert
Pset_CasaProvenance - DesignSource: Casa Sobreposta / configuration.json; ReferenceFile: 260617_CasaDFL_Estrutura_Terreno.ifc; ConstructionBasis: DESIGN_ASSUMPTION; Note: Study guard 1.10 m; twin handrails at 0.70 and 0.90 m on ramp; loads and fixings unverified.
Name | In
Pódio · guarda sul | 00 · Habitação e estacionamento
Pódio · guarda poente sul | 00 · Habitação e estacionamento
Pódio · guarda poente norte | 00 · Habitação e estacionamento
Pódio · guarda norte | 00 · Habitação e estacionamento
2 x Jardim · corrimão poente | 00 · Habitação e estacionamento
2 x Jardim · guarda do patamar | 00 · Habitação e estacionamento
6 x Acesso · guarda lateral | Lares · Rua das Mercês · artigo 4771

# IfcRoof, Cobertura de telha · duas águas 30 graus
In: 00 · Habitação e estacionamento
PredefinedType: GABLE_ROOF; Material: Madeira / Bauholz
Pset_CasaProvenance - DesignSource: Casa Sobreposta / configuration.json; ReferenceFile: 260617_CasaDFL_Estrutura_Terreno.ifc; ConstructionBasis: DESIGN_ASSUMPTION
Pset_CasaRoof - Pitch_deg: 30; StoreysAboveGround: 1; AtticFloor: no; Interior: Open to sloping timber deck; no ceiling or upper floor; StructuralStatus: Concept only; 200 km/h verification from R05 greenhouse does not apply; CoversWholePodium: yes; RoofPlanLength_m: 38.8; RoofPlanWidth_m: 8.9; ThermalBuildUp: 20 mm timber deck + 160 mm insulation + membrane + ventilated battens + clay tile; assumptions

# IfcSanitaryTerminal (5)
In: 00 · Habitação e estacionamento
Material: Cerâmica sanitária — esquema
Pset_CasaProvenance - DesignSource: Casa Sobreposta / configuration.json; ReferenceFile: 260617_CasaDFL_Estrutura_Terreno.ifc; ConstructionBasis: DESIGN_ASSUMPTION; Note: Schematic fixture, not a manufacturer object.
Name | PredefinedType
Banheira | BATH
Lavatório 1 | WASHHANDBASIN
Lavatório 2 | WASHHANDBASIN
Sanita | TOILETPAN
Bancada de cozinha | TOILETPAN

# IfcSlab (9)
Pset_CasaProvenance - DesignSource: Casa Sobreposta / configuration.json; ReferenceFile: 260617_CasaDFL_Estrutura_Terreno.ifc; ConstructionBasis: DESIGN_ASSUMPTION
Name | In | PredefinedType | Material
Cisterna · laje de fundo 200 mm | -01 · Cisterna sob o terraço | BASESLAB | Betão armado / Stahlbeton
Pódio · laje da casa 250 mm | 00 · Habitação e estacionamento | FLOOR | Betão armado / Stahlbeton | Pset_CasaProvenance - Note: Suspended slab on discrete piers and grade beams. Natural sloping terrain retained below; no fill platform. Sizes unverified.
Pódio · terraço e faixa de proteção sul | 00 · Habitação e estacionamento | FLOOR | Betão armado / Stahlbeton | Pset_CasaProvenance - Note: Terrace 40 mm below house. Entire terrace suspended above natural terrain; west end above cistern. No continuous retaining plinth.
Jardim · patamar poente | 00 · Habitação e estacionamento | LANDING | Betão armado / Stahlbeton
2 x Contentor · piso ou teto | 00 · Habitação e estacionamento | FLOOR | Contentor · pintura 1
2 x Contentor · piso ou teto | 00 · Habitação e estacionamento | FLOOR | Contentor · pintura 2
Acesso · laje suspensa sobre o terreno natural | Lares · Rua das Mercês · artigo 4771 | FLOOR | Betão armado / Stahlbeton | Pset_CasaProvenance - Note: R07 concept geometry; dimensions and connections not structurally verified.

# IfcStair, Jardim · escada pela fachada poente
In: 00 · Habitação e estacionamento
PredefinedType: STRAIGHT_RUN_STAIR
Pset_CasaProvenance - DesignSource: Casa Sobreposta / configuration.json; ReferenceFile: 260617_CasaDFL_Estrutura_Terreno.ifc; ConstructionBasis: DESIGN_ASSUMPTION; Note: West-facing descent; no south opening. Survey-based concept.

# IfcStairFlight, Jardim · lanço poente
In: 00 · Habitação e estacionamento
NumberOfRisers: 19; NumberOfTreads: 18; RiserHeight: 0.166316 m; TreadLength: 0.3 m; PredefinedType: STRAIGHT; Material: Betão armado / Stahlbeton
Pset_CasaProvenance - DesignSource: Casa Sobreposta / configuration.json; ReferenceFile: 260617_CasaDFL_Estrutura_Terreno.ifc; ConstructionBasis: DESIGN_ASSUMPTION

# IfcTank: RAINWATER_CISTERN, Cisterna · reservatório pluvial de estudo
In: -01 · Cisterna sob o terraço
PredefinedType: STORAGE
Pset_CasaProvenance - DesignSource: Casa Sobreposta / configuration.json; ReferenceFile: 260617_CasaDFL_Estrutura_Terreno.ifc; ConstructionBasis: DESIGN_ASSUMPTION; Note: Composite concrete vessel; provisional geometry only. No ordinary occupancy or stair access. Water depth and capacity to design.
Pset_CasaCistern - InternalPlanArea_m2: 17.8125; WaterDepthAssumed_m: 2; GeometricWaterVolume_m3: 35.625; SoffitClearanceAboveWater_m: 0.31; Status: Provisional water envelope; hydrostatic, uplift, watertightness, filtration, overflow and maintenance design pending

# IfcWall (89)
In: 00 · Habitação e estacionamento
Pset_CasaProvenance - DesignSource: Casa Sobreposta / configuration.json; ReferenceFile: 260617_CasaDFL_Estrutura_Terreno.ifc
Name | Material | ConstructionBasis | Pset_CasaProvenance, Note
Divisória 1 · OSB 22 mm nas duas faces | OSB, Lã mineral / Mineralwolle 2 | ADAPTED_REFERENCE | Original centreline/door positions preserved; schematic footprint widened 20 mm per side. 22 mm OSB linings; mineral wool core; stud layout not developed.
Divisória 2 · OSB 22 mm nas duas faces | OSB, Lã mineral / Mineralwolle 2 | ADAPTED_REFERENCE | Original centreline/door positions preserved; schematic footprint widened 20 mm per side. 22 mm OSB linings; mineral wool core; stud layout not developed.
Divisória 3 · OSB 22 mm nas duas faces | OSB, Lã mineral / Mineralwolle 2 | ADAPTED_REFERENCE | Original centreline/door positions preserved; schematic footprint widened 20 mm per side. 22 mm OSB linings; mineral wool core; stud layout not developed.
Divisória 4 · OSB 22 mm nas duas faces | OSB, Lã mineral / Mineralwolle 2 | ADAPTED_REFERENCE | Original centreline/door positions preserved; schematic footprint widened 20 mm per side. 22 mm OSB linings; mineral wool core; stud layout not developed.
Fachada norte · sandwich Casa DFL | Aço pintado / Stahl lackiert 0.005 m, Lã mineral / Mineralwolle 2 0.12 m, Aço pintado / Stahl lackiert 0.00516 m | ADAPTED_REFERENCE | Pset_CasaAssembly - OverallThickness_m: 0.13016; SourceModelSkinThicknesses_m: 0.005 / 0.00516; Core_m: 0.12; Note: Source geometry retained; commercial sheet specification not established.
Separação do estacionamento | Aço pintado / Stahl lackiert 0.005 m, Lã mineral / Mineralwolle 2 0.12 m, Aço pintado / Stahl lackiert 0.00516 m | ADAPTED_REFERENCE | Pset_CasaAssembly - OverallThickness_m: 0.13016; SourceModelSkinThicknesses_m: 0.005 / 0.00516; Core_m: 0.12; Note: Source geometry retained; commercial sheet specification not established.
Painel opaco sul 0 | Aço pintado / Stahl lackiert 0.005 m, Lã mineral / Mineralwolle 2 0.12 m, Aço pintado / Stahl lackiert 0.00516 m | ADAPTED_REFERENCE | Pset_CasaAssembly - OverallThickness_m: 0.13016; SourceModelSkinThicknesses_m: 0.005 / 0.00516; Core_m: 0.12; Note: Source geometry retained; commercial sheet specification not established.
Painel opaco sul 1 | Aço pintado / Stahl lackiert 0.005 m, Lã mineral / Mineralwolle 2 0.12 m, Aço pintado / Stahl lackiert 0.00516 m | ADAPTED_REFERENCE | Pset_CasaAssembly - OverallThickness_m: 0.13016; SourceModelSkinThicknesses_m: 0.005 / 0.00516; Core_m: 0.12; Note: Source geometry retained; commercial sheet specification not established.
Painel opaco sul 3 | Aço pintado / Stahl lackiert 0.005 m, Lã mineral / Mineralwolle 2 0.12 m, Aço pintado / Stahl lackiert 0.00516 m | ADAPTED_REFERENCE | Pset_CasaAssembly - OverallThickness_m: 0.13016; SourceModelSkinThicknesses_m: 0.005 / 0.00516; Core_m: 0.12; Note: Source geometry retained; commercial sheet specification not established.
Painel opaco sul 5 | Aço pintado / Stahl lackiert 0.005 m, Lã mineral / Mineralwolle 2 0.12 m, Aço pintado / Stahl lackiert 0.00516 m | ADAPTED_REFERENCE | Pset_CasaAssembly - OverallThickness_m: 0.13016; SourceModelSkinThicknesses_m: 0.005 / 0.00516; Core_m: 0.12; Note: Source geometry retained; commercial sheet specification not established.
Painel opaco sul 7 | Aço pintado / Stahl lackiert 0.005 m, Lã mineral / Mineralwolle 2 0.12 m, Aço pintado / Stahl lackiert 0.00516 m | ADAPTED_REFERENCE | Pset_CasaAssembly - OverallThickness_m: 0.13016; SourceModelSkinThicknesses_m: 0.005 / 0.00516; Core_m: 0.12; Note: Source geometry retained; commercial sheet specification not established.
Painel opaco sul 9 | Aço pintado / Stahl lackiert 0.005 m, Lã mineral / Mineralwolle 2 0.12 m, Aço pintado / Stahl lackiert 0.00516 m | ADAPTED_REFERENCE | Pset_CasaAssembly - OverallThickness_m: 0.13016; SourceModelSkinThicknesses_m: 0.005 / 0.00516; Core_m: 0.12; Note: Source geometry retained; commercial sheet specification not established.
Painel opaco sul 11 | Aço pintado / Stahl lackiert 0.005 m, Lã mineral / Mineralwolle 2 0.12 m, Aço pintado / Stahl lackiert 0.00516 m | ADAPTED_REFERENCE | Pset_CasaAssembly - OverallThickness_m: 0.13016; SourceModelSkinThicknesses_m: 0.005 / 0.00516; Core_m: 0.12; Note: Source geometry retained; commercial sheet specification not established.
2 x Fachada · remate sob frechal | Madeira / Bauholz | DESIGN_ASSUMPTION
74 x Divisória · prolongamento até ao forro | OSB | DESIGN_ASSUMPTION | R07 concept geometry; dimensions and connections not structurally verified.

# IfcWall: Acesso · gabião -1 12.0 · núcleo de pedra
In: Lares · Rua das Mercês · artigo 4771
PredefinedType: USERDEFINED; Material: Gabião · enchimento
Pset_CasaProvenance - DesignSource: Casa Sobreposta / configuration.json; ReferenceFile: 260617_CasaDFL_Estrutura_Terreno.ifc; ConstructionBasis: DESIGN_ASSUMPTION; Note: Concept gabion envelope; mesh gauge, foundation, filter and retaining capacity to design.
Pset_CasaBoundary - BaseSurveyLevel_m: 14.3333; TopSurveyLevel_m: 15.733; Status: CONCEPT_NOT_SIZED

# IfcWall: Acesso · gabião -1 15.0 · núcleo de pedra
In: Lares · Rua das Mercês · artigo 4771
PredefinedType: USERDEFINED; Material: Gabião · enchimento
Pset_CasaProvenance - DesignSource: Casa Sobreposta / configuration.json; ReferenceFile: 260617_CasaDFL_Estrutura_Terreno.ifc; ConstructionBasis: DESIGN_ASSUMPTION; Note: Concept gabion envelope; mesh gauge, foundation, filter and retaining capacity to design.
Pset_CasaBoundary - BaseSurveyLevel_m: 14.5072; TopSurveyLevel_m: 15.736; Status: CONCEPT_NOT_SIZED

# IfcWall: Acesso · gabião -1 18.0 · núcleo de pedra
In: Lares · Rua das Mercês · artigo 4771
PredefinedType: USERDEFINED; Material: Gabião · enchimento
Pset_CasaProvenance - DesignSource: Casa Sobreposta / configuration.json; ReferenceFile: 260617_CasaDFL_Estrutura_Terreno.ifc; ConstructionBasis: DESIGN_ASSUMPTION; Note: Concept gabion envelope; mesh gauge, foundation, filter and retaining capacity to design.
Pset_CasaBoundary - BaseSurveyLevel_m: 14.6824; TopSurveyLevel_m: 15.739; Status: CONCEPT_NOT_SIZED

# IfcWall: Acesso · gabião -1 21.0 · núcleo de pedra
In: Lares · Rua das Mercês · artigo 4771
PredefinedType: USERDEFINED; Material: Gabião · enchimento
Pset_CasaProvenance - DesignSource: Casa Sobreposta / configuration.json; ReferenceFile: 260617_CasaDFL_Estrutura_Terreno.ifc; ConstructionBasis: DESIGN_ASSUMPTION; Note: Concept gabion envelope; mesh gauge, foundation, filter and retaining capacity to design.
Pset_CasaBoundary - BaseSurveyLevel_m: 14.8576; TopSurveyLevel_m: 15.8609; Status: CONCEPT_NOT_SIZED

# IfcWall: Acesso · gabião -1 24.0 · núcleo de pedra
In: Lares · Rua das Mercês · artigo 4771
PredefinedType: USERDEFINED; Material: Gabião · enchimento
Pset_CasaProvenance - DesignSource: Casa Sobreposta / configuration.json; ReferenceFile: 260617_CasaDFL_Estrutura_Terreno.ifc; ConstructionBasis: DESIGN_ASSUMPTION; Note: Concept gabion envelope; mesh gauge, foundation, filter and retaining capacity to design.
Pset_CasaBoundary - BaseSurveyLevel_m: 15.0114; TopSurveyLevel_m: 16.0133; Status: CONCEPT_NOT_SIZED

# IfcWall: Acesso · gabião -1 27.0 · núcleo de pedra
In: Lares · Rua das Mercês · artigo 4771
PredefinedType: USERDEFINED; Material: Gabião · enchimento
Pset_CasaProvenance - DesignSource: Casa Sobreposta / configuration.json; ReferenceFile: 260617_CasaDFL_Estrutura_Terreno.ifc; ConstructionBasis: DESIGN_ASSUMPTION; Note: Concept gabion envelope; mesh gauge, foundation, filter and retaining capacity to design.
Pset_CasaBoundary - BaseSurveyLevel_m: 15.2016; TopSurveyLevel_m: 16.1742; Status: CONCEPT_NOT_SIZED

# IfcWall: Acesso · gabião -1 30.0 · núcleo de pedra
In: Lares · Rua das Mercês · artigo 4771
PredefinedType: USERDEFINED; Material: Gabião · enchimento
Pset_CasaProvenance - DesignSource: Casa Sobreposta / configuration.json; ReferenceFile: 260617_CasaDFL_Estrutura_Terreno.ifc; ConstructionBasis: DESIGN_ASSUMPTION; Note: Concept gabion envelope; mesh gauge, foundation, filter and retaining capacity to design.
Pset_CasaBoundary - BaseSurveyLevel_m: 15.3761; TopSurveyLevel_m: 16.2987; Status: CONCEPT_NOT_SIZED

# IfcWall: Acesso · gabião -1 33.0 · núcleo de pedra
In: Lares · Rua das Mercês · artigo 4771
PredefinedType: USERDEFINED; Material: Gabião · enchimento
Pset_CasaProvenance - DesignSource: Casa Sobreposta / configuration.json; ReferenceFile: 260617_CasaDFL_Estrutura_Terreno.ifc; ConstructionBasis: DESIGN_ASSUMPTION; Note: Concept gabion envelope; mesh gauge, foundation, filter and retaining capacity to design.
Pset_CasaBoundary - BaseSurveyLevel_m: 15.5502; TopSurveyLevel_m: 16.3676; Status: CONCEPT_NOT_SIZED

# IfcWall: Acesso · gabião -1 9.0 · núcleo de pedra
In: Lares · Rua das Mercês · artigo 4771
PredefinedType: USERDEFINED; Material: Gabião · enchimento
Pset_CasaProvenance - DesignSource: Casa Sobreposta / configuration.json; ReferenceFile: 260617_CasaDFL_Estrutura_Terreno.ifc; ConstructionBasis: DESIGN_ASSUMPTION; Note: Concept gabion envelope; mesh gauge, foundation, filter and retaining capacity to design.
Pset_CasaBoundary - BaseSurveyLevel_m: 14.2084; TopSurveyLevel_m: 15.73; Status: CONCEPT_NOT_SIZED

# IfcWall: Acesso · gabião 1 12.0 · núcleo de pedra
In: Lares · Rua das Mercês · artigo 4771
PredefinedType: USERDEFINED; Material: Gabião · enchimento
Pset_CasaProvenance - DesignSource: Casa Sobreposta / configuration.json; ReferenceFile: 260617_CasaDFL_Estrutura_Terreno.ifc; ConstructionBasis: DESIGN_ASSUMPTION; Note: Concept gabion envelope; mesh gauge, foundation, filter and retaining capacity to design.
Pset_CasaBoundary - BaseSurveyLevel_m: 14.8446; TopSurveyLevel_m: 15.733; Status: CONCEPT_NOT_SIZED

# IfcWall: Acesso · gabião 1 15.0 · núcleo de pedra
In: Lares · Rua das Mercês · artigo 4771
PredefinedType: USERDEFINED; Material: Gabião · enchimento
Pset_CasaProvenance - DesignSource: Casa Sobreposta / configuration.json; ReferenceFile: 260617_CasaDFL_Estrutura_Terreno.ifc; ConstructionBasis: DESIGN_ASSUMPTION; Note: Concept gabion envelope; mesh gauge, foundation, filter and retaining capacity to design.
Pset_CasaBoundary - BaseSurveyLevel_m: 15.0671; TopSurveyLevel_m: 15.7374; Status: CONCEPT_NOT_SIZED

# IfcWall: Acesso · gabião 1 18.0 · núcleo de pedra
In: Lares · Rua das Mercês · artigo 4771
PredefinedType: USERDEFINED; Material: Gabião · enchimento
Pset_CasaProvenance - DesignSource: Casa Sobreposta / configuration.json; ReferenceFile: 260617_CasaDFL_Estrutura_Terreno.ifc; ConstructionBasis: DESIGN_ASSUMPTION; Note: Concept gabion envelope; mesh gauge, foundation, filter and retaining capacity to design.
Pset_CasaBoundary - BaseSurveyLevel_m: 15.266; TopSurveyLevel_m: 15.8642; Status: CONCEPT_NOT_SIZED

# IfcWall: Acesso · gabião 1 21.0 · núcleo de pedra
In: Lares · Rua das Mercês · artigo 4771
PredefinedType: USERDEFINED; Material: Gabião · enchimento
Pset_CasaProvenance - DesignSource: Casa Sobreposta / configuration.json; ReferenceFile: 260617_CasaDFL_Estrutura_Terreno.ifc; ConstructionBasis: DESIGN_ASSUMPTION; Note: Concept gabion envelope; mesh gauge, foundation, filter and retaining capacity to design.
Pset_CasaBoundary - BaseSurveyLevel_m: 15.269; TopSurveyLevel_m: 16.0325; Status: CONCEPT_NOT_SIZED

# IfcWall: Acesso · gabião 1 24.0 · núcleo de pedra
In: Lares · Rua das Mercês · artigo 4771
PredefinedType: USERDEFINED; Material: Gabião · enchimento
Pset_CasaProvenance - DesignSource: Casa Sobreposta / configuration.json; ReferenceFile: 260617_CasaDFL_Estrutura_Terreno.ifc; ConstructionBasis: DESIGN_ASSUMPTION; Note: Concept gabion envelope; mesh gauge, foundation, filter and retaining capacity to design.
Pset_CasaBoundary - BaseSurveyLevel_m: 15.3909; TopSurveyLevel_m: 16.2135; Status: CONCEPT_NOT_SIZED

# IfcWall: Acesso · gabião 1 27.0 · núcleo de pedra
In: Lares · Rua das Mercês · artigo 4771
PredefinedType: USERDEFINED; Material: Gabião · enchimento
Pset_CasaProvenance - DesignSource: Casa Sobreposta / configuration.json; ReferenceFile: 260617_CasaDFL_Estrutura_Terreno.ifc; ConstructionBasis: DESIGN_ASSUMPTION; Note: Concept gabion envelope; mesh gauge, foundation, filter and retaining capacity to design.
Pset_CasaBoundary - BaseSurveyLevel_m: 15.5433; TopSurveyLevel_m: 16.3757; Status: CONCEPT_NOT_SIZED

# IfcWall: Acesso · gabião 1 30.0 · núcleo de pedra
In: Lares · Rua das Mercês · artigo 4771
PredefinedType: USERDEFINED; Material: Gabião · enchimento
Pset_CasaProvenance - DesignSource: Casa Sobreposta / configuration.json; ReferenceFile: 260617_CasaDFL_Estrutura_Terreno.ifc; ConstructionBasis: DESIGN_ASSUMPTION; Note: Concept gabion envelope; mesh gauge, foundation, filter and retaining capacity to design.
Pset_CasaBoundary - BaseSurveyLevel_m: 15.7042; TopSurveyLevel_m: 16.5071; Status: CONCEPT_NOT_SIZED

# IfcWall: Acesso · gabião 1 33.0 · núcleo de pedra
In: Lares · Rua das Mercês · artigo 4771
PredefinedType: USERDEFINED; Material: Gabião · enchimento
Pset_CasaProvenance - DesignSource: Casa Sobreposta / configuration.json; ReferenceFile: 260617_CasaDFL_Estrutura_Terreno.ifc; ConstructionBasis: DESIGN_ASSUMPTION; Note: Concept gabion envelope; mesh gauge, foundation, filter and retaining capacity to design.
Pset_CasaBoundary - BaseSurveyLevel_m: 15.8287; TopSurveyLevel_m: 16.6061; Status: CONCEPT_NOT_SIZED

# IfcWall: Acesso · gabião 1 9.0 · núcleo de pedra
In: Lares · Rua das Mercês · artigo 4771
PredefinedType: USERDEFINED; Material: Gabião · enchimento
Pset_CasaProvenance - DesignSource: Casa Sobreposta / configuration.json; ReferenceFile: 260617_CasaDFL_Estrutura_Terreno.ifc; ConstructionBasis: DESIGN_ASSUMPTION; Note: Concept gabion envelope; mesh gauge, foundation, filter and retaining capacity to design.
Pset_CasaBoundary - BaseSurveyLevel_m: 14.8084; TopSurveyLevel_m: 15.73; Status: CONCEPT_NOT_SIZED

# IfcWall: Cisterna · parede nascente
In: -01 · Cisterna sob o terraço
PredefinedType: USERDEFINED; Material: Betão armado / Stahlbeton
Pset_CasaProvenance - DesignSource: Casa Sobreposta / configuration.json; ReferenceFile: 260617_CasaDFL_Estrutura_Terreno.ifc; ConstructionBasis: DESIGN_ASSUMPTION; Note: 250 mm RC study wall, waterproofing and joints to detail; no retaining capacity asserted.

# IfcWall: Cisterna · parede norte
In: -01 · Cisterna sob o terraço
PredefinedType: USERDEFINED; Material: Betão armado / Stahlbeton
Pset_CasaProvenance - DesignSource: Casa Sobreposta / configuration.json; ReferenceFile: 260617_CasaDFL_Estrutura_Terreno.ifc; ConstructionBasis: DESIGN_ASSUMPTION; Note: 250 mm RC study wall, waterproofing and joints to detail; no retaining capacity asserted.

# IfcWall: Cisterna · parede poente
In: -01 · Cisterna sob o terraço
PredefinedType: USERDEFINED; Material: Betão armado / Stahlbeton
Pset_CasaProvenance - DesignSource: Casa Sobreposta / configuration.json; ReferenceFile: 260617_CasaDFL_Estrutura_Terreno.ifc; ConstructionBasis: DESIGN_ASSUMPTION; Note: 250 mm RC study wall, waterproofing and joints to detail; no retaining capacity asserted.

# IfcWall: Cisterna · parede sul
In: -01 · Cisterna sob o terraço
PredefinedType: USERDEFINED; Material: Betão armado / Stahlbeton
Pset_CasaProvenance - DesignSource: Casa Sobreposta / configuration.json; ReferenceFile: 260617_CasaDFL_Estrutura_Terreno.ifc; ConstructionBasis: DESIGN_ASSUMPTION; Note: 250 mm RC study wall, waterproofing and joints to detail; no retaining capacity asserted.

# IfcWall: Limite north · gabião 10 · núcleo de pedra
In: Lares · Rua das Mercês · artigo 4771
PredefinedType: USERDEFINED; Material: Gabião · enchimento
Pset_CasaProvenance - DesignSource: Casa Sobreposta / configuration.json; ReferenceFile: 260617_CasaDFL_Estrutura_Terreno.ifc; ConstructionBasis: DESIGN_ASSUMPTION; Note: Concept gabion envelope; mesh gauge, foundation, filter and retaining capacity to design.
Pset_CasaBoundary - BaseSurveyLevel_m: 14; TopSurveyLevel_m: 14.9; Status: CONCEPT_NOT_SIZED

# IfcWall: Limite north · gabião 11 · núcleo de pedra
In: Lares · Rua das Mercês · artigo 4771
PredefinedType: USERDEFINED; Material: Gabião · enchimento
Pset_CasaProvenance - DesignSource: Casa Sobreposta / configuration.json; ReferenceFile: 260617_CasaDFL_Estrutura_Terreno.ifc; ConstructionBasis: DESIGN_ASSUMPTION; Note: Concept gabion envelope; mesh gauge, foundation, filter and retaining capacity to design.
Pset_CasaBoundary - BaseSurveyLevel_m: 14.25; TopSurveyLevel_m: 15; Status: CONCEPT_NOT_SIZED

# IfcWall: Limite north · gabião 12 · núcleo de pedra
In: Lares · Rua das Mercês · artigo 4771
PredefinedType: USERDEFINED; Material: Gabião · enchimento
Pset_CasaProvenance - DesignSource: Casa Sobreposta / configuration.json; ReferenceFile: 260617_CasaDFL_Estrutura_Terreno.ifc; ConstructionBasis: DESIGN_ASSUMPTION; Note: Concept gabion envelope; mesh gauge, foundation, filter and retaining capacity to design.
Pset_CasaBoundary - BaseSurveyLevel_m: 14.25; TopSurveyLevel_m: 15.1; Status: CONCEPT_NOT_SIZED

# IfcWall: Limite north · gabião 13 · núcleo de pedra
In: Lares · Rua das Mercês · artigo 4771
PredefinedType: USERDEFINED; Material: Gabião · enchimento
Pset_CasaProvenance - DesignSource: Casa Sobreposta / configuration.json; ReferenceFile: 260617_CasaDFL_Estrutura_Terreno.ifc; ConstructionBasis: DESIGN_ASSUMPTION; Note: Concept gabion envelope; mesh gauge, foundation, filter and retaining capacity to design.
